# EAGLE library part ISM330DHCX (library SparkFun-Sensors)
ISM330DHCX 6DoF The ISM330DHCX is a system-in-package featuring a high-performance 3D digital accelerometer and 3D digital gyroscope tailored for Industry 4.0 applications.

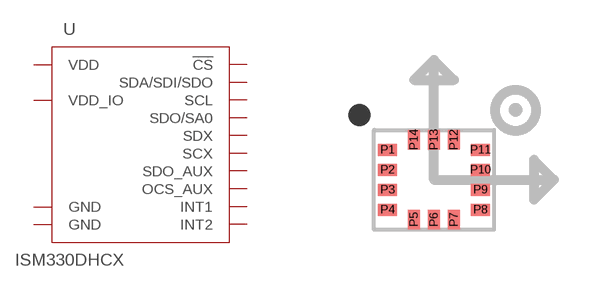
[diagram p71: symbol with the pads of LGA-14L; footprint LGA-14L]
Designator prefix U

## ISM330DHCX (PROD_ID: IC-16693)  [LGA-14L]
P1  SDO/SA0
P2  SDX
P3  SCX
P4  INT1
P5  VDD_IO  pwr
P6  GND  pwr
P7  GND  pwr
P8  VDD  pwr
P9  INT2
P10  OCS_AUX
P11  SDO_AUX
P12  !CS!
P13  SCL
P14  SDA/SDI/SDO

## Footprint LGA-14L (pad centres in mm)
Physical Characteristics Overall Size: 2.5mm x 3mm Total Pins: 14 Pad Size: .475mm x . 25mm Pad Pitch: .5mm
smd 0.48 x 0.3: P1 -1.163,0.75; P2 -1.163,0.25; P3 -1.163,-0.25; P4 -1.163,-0.75; P8 1.163,-0.75; P9 1.163,-0.25; P10 1.163,0.25; P11 1.163,0.75
smd 0.3 x 0.48: P5 -0.5,-1; P6 0,-1; P7 0.5,-1; P12 0.5,1; P13 0,1; P14 -0.5,1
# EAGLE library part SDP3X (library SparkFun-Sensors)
Differential Pressure Sensor SDP3x The World's Smallest Differential Pressure Sensor The SDP3x is the world's smallest differential pressure sensor. It measures just 5 mm x 8 mm x 5 mm, opening up new dimensions of integration and application possibilities. The sensor is based on the next generation of the CMOSens® sensor chip and is the heart of Sensirion's new sensor platform for measuring differential pressure and mass flow.

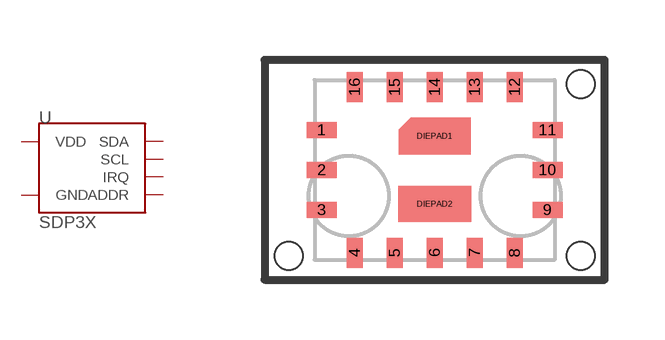
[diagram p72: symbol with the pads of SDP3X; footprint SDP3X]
Designator prefix U

## SDP3X_SDP31 (PROD_ID: IC-15720; VALUE: SDP31)  [SDP3X]
1  GND  pwr
2  GND  pwr
3  GND  pwr
4  IRQ  out
5  SCL
6  GND  pwr
7  VDD  pwr
8  SDA
9  ADDR
10  GND  pwr
11  GND  pwr
DIEPAD1  GND  pwr
DIEPAD2  GND  pwr

## Footprint SDP3X (pad centres in mm)
SDP31
smd 0.75 x 0.4: 1 -2.825,1; 2 -2.825,0; 3 -2.825,-1; 9 2.825,-1; 10 2.825,0; 11 2.825,1
smd 0.4 x 0.75: 4 -2,-2.075; 5 -1,-2.075; 6 0,-2.075; 7 1,-2.075; 8 2,-2.075; 12 2,2.075; 13 1,2.075; 14 0,2.075; 15 -1,2.075; 16 -2,2.075
smd 0.61 x 0.305: DIEPAD1 0,0.85; DIEPAD2 0,-0.85
hole 0.7 at -3.65,-2.15
hole 0.7 at 3.65,-2.15
hole 0.7 at 3.65,2.15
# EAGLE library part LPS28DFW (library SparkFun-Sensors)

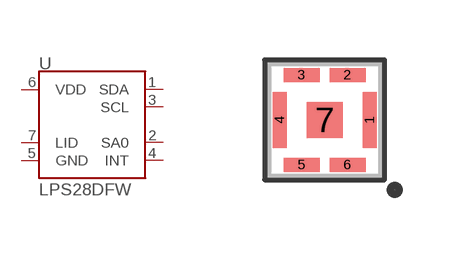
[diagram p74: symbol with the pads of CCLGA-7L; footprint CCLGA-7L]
Designator prefix U

## LPS28DFW (PROD_ID: IC-17197)  [CCLGA-7L]
1  SDA
2  SA0  in
3  SCL  in
4  INT  out
5  GND  pwr
6  VDD  pwr
7  LID  pas

## Footprint CCLGA-7L (pad centres in mm)
smd 0.35 x 1.4: 1 1.125,0; 4 -1.125,0
smd 0.9 x 0.35: 2 0.575,1.125; 3 -0.575,1.125; 5 -0.575,-1.125; 6 0.575,-1.125
smd 0.9 x 0.9: 7 0,0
